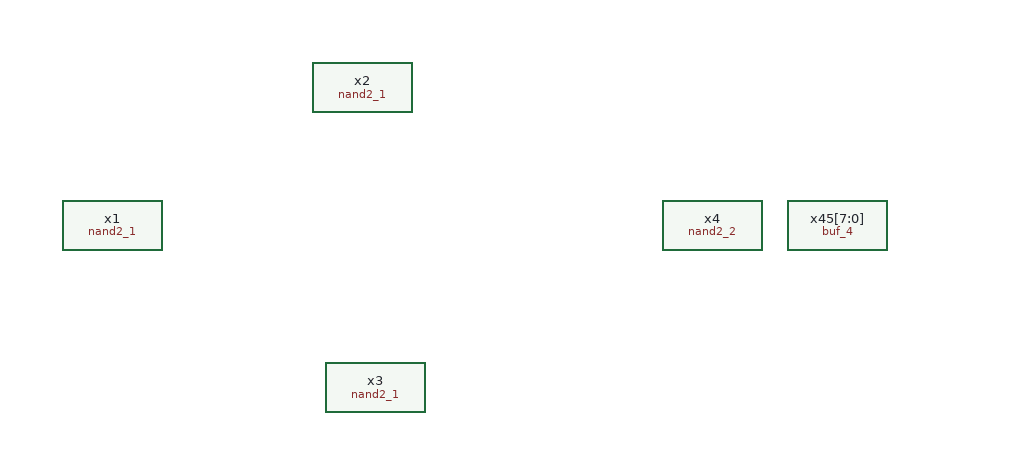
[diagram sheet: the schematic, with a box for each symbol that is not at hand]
v {xschem version=3.4.5 file_version=1.2
}
G {}
K {}
V {}
S {}
E {}
C {sky130_stdcells/nand2_1.sym} -30 -40 0 0 {name=x1 VGND=vss VNB=vss VPB=vdd VPWR=vdd prefix=sky130_fd_sc_hd__ }
C {sky130_stdcells/nand2_1.sym} 170 -150 0 0 {name=x2 VGND=vss VNB=vss VPB=vdd VPWR=vdd prefix=sky130_fd_sc_hd__ }
C {sky130_stdcells/nand2_1.sym} 180 90 0 0 {name=x3 VGND=vss VNB=vss VPB=vdd VPWR=vdd prefix=sky130_fd_sc_hd__ }
C {sky130_stdcells/nand2_2.sym} 450 -40 0 0 {name=x4 VGND=vss VNB=vss VPB=vdd VPWR=vdd prefix=sky130_fd_sc_hd__ }
C {sky130_stdcells/buf_4.sym} 550 -40 0 0 {name=x45[7:0] VGND=vss VNB=vss VPB=vdd VPWR=vdd prefix=sky130_fd_sc_hd__ }
